One B-rep face of a CAD part: STEP entity #77526.
In plain terms, the planar face has unit normal (0, 0, 1).
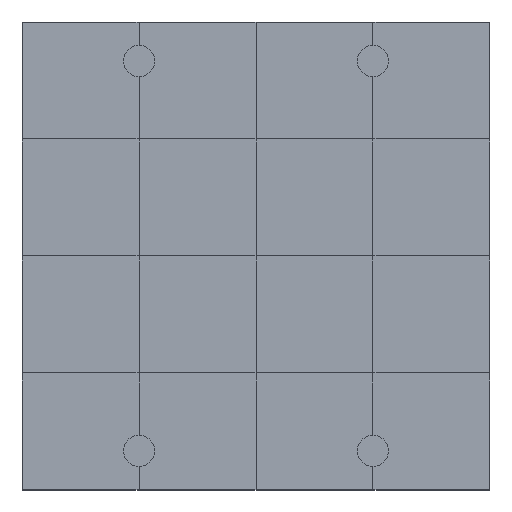
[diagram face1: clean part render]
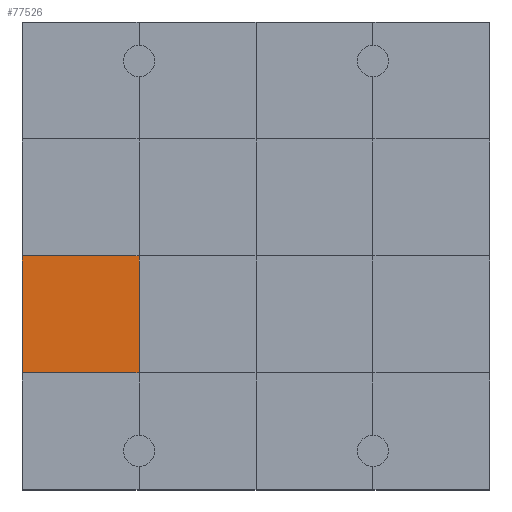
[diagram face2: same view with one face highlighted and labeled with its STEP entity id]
Its self-contained STEP definition (entity closure, numbers rounded to 3 decimals):
#77076 = VERTEX_POINT('',#77077);
#77077 = CARTESIAN_POINT('',(0.,3.,1.2));
#77091 = PLANE('',#77092);
#77092 = AXIS2_PLACEMENT_3D('',#77093,#77094,#77095);
#77093 = CARTESIAN_POINT('',(0.,3.,0.));
#77094 = DIRECTION('',(1.,0.,-0.));
#77095 = DIRECTION('',(0.,0.,1.));
#77117 = PLANE('',#77118);
#77118 = AXIS2_PLACEMENT_3D('',#77119,#77120,#77121);
#77119 = CARTESIAN_POINT('',(0.,0.,1.2));
#77120 = DIRECTION('',(0.,0.,1.));
#77121 = DIRECTION('',(1.,0.,-0.));
#77268 = VERTEX_POINT('',#77269);
#77269 = CARTESIAN_POINT('',(3.,3.,1.2));
#77290 = EDGE_CURVE('',#77076,#77268,#77291,.T.);
#77291 = SURFACE_CURVE('',#77292,(#77296,#77303),.PCURVE_S1.);
#77292 = LINE('',#77293,#77294);
#77293 = CARTESIAN_POINT('',(0.,3.,1.2));
#77294 = VECTOR('',#77295,1.);
#77295 = DIRECTION('',(1.,0.,-0.));
#77296 = PCURVE('',#77117,#77297);
#77297 = DEFINITIONAL_REPRESENTATION('',(#77298),#77302);
#77298 = LINE('',#77299,#77300);
#77299 = CARTESIAN_POINT('',(0.,3.));
#77300 = VECTOR('',#77301,1.);
#77301 = DIRECTION('',(1.,0.));
#77302 = ( GEOMETRIC_REPRESENTATION_CONTEXT(2) 
PARAMETRIC_REPRESENTATION_CONTEXT() REPRESENTATION_CONTEXT('2D SPACE',''
  ) );
#77303 = PCURVE('',#77304,#77309);
#77304 = PLANE('',#77305);
#77305 = AXIS2_PLACEMENT_3D('',#77306,#77307,#77308);
#77306 = CARTESIAN_POINT('',(0.,3.,1.2));
#77307 = DIRECTION('',(0.,0.,1.));
#77308 = DIRECTION('',(1.,0.,-0.));
#77309 = DEFINITIONAL_REPRESENTATION('',(#77310),#77314);
#77310 = LINE('',#77311,#77312);
#77311 = CARTESIAN_POINT('',(0.,0.));
#77312 = VECTOR('',#77313,1.);
#77313 = DIRECTION('',(1.,0.));
#77314 = ( GEOMETRIC_REPRESENTATION_CONTEXT(2) 
PARAMETRIC_REPRESENTATION_CONTEXT() REPRESENTATION_CONTEXT('2D SPACE',''
  ) );
#77349 = VERTEX_POINT('',#77350);
#77350 = CARTESIAN_POINT('',(0.,6.,1.2));
#77376 = EDGE_CURVE('',#77076,#77349,#77377,.T.);
#77377 = SURFACE_CURVE('',#77378,(#77382,#77389),.PCURVE_S1.);
#77378 = LINE('',#77379,#77380);
#77379 = CARTESIAN_POINT('',(0.,3.,1.2));
#77380 = VECTOR('',#77381,1.);
#77381 = DIRECTION('',(-0.,1.,0.));
#77382 = PCURVE('',#77091,#77383);
#77383 = DEFINITIONAL_REPRESENTATION('',(#77384),#77388);
#77384 = LINE('',#77385,#77386);
#77385 = CARTESIAN_POINT('',(1.2,0.));
#77386 = VECTOR('',#77387,1.);
#77387 = DIRECTION('',(0.,-1.));
#77388 = ( GEOMETRIC_REPRESENTATION_CONTEXT(2) 
PARAMETRIC_REPRESENTATION_CONTEXT() REPRESENTATION_CONTEXT('2D SPACE',''
  ) );
#77389 = PCURVE('',#77304,#77390);
#77390 = DEFINITIONAL_REPRESENTATION('',(#77391),#77395);
#77391 = LINE('',#77392,#77393);
#77392 = CARTESIAN_POINT('',(0.,0.));
#77393 = VECTOR('',#77394,1.);
#77394 = DIRECTION('',(0.,1.));
#77395 = ( GEOMETRIC_REPRESENTATION_CONTEXT(2) 
PARAMETRIC_REPRESENTATION_CONTEXT() REPRESENTATION_CONTEXT('2D SPACE',''
  ) );
#77526 = ADVANCED_FACE('',(#77527),#77304,.T.);
#77527 = FACE_BOUND('',#77528,.T.);
#77528 = EDGE_LOOP('',(#77529,#77530,#77531,#77559));
#77529 = ORIENTED_EDGE('',*,*,#77376,.F.);
#77530 = ORIENTED_EDGE('',*,*,#77290,.T.);
#77531 = ORIENTED_EDGE('',*,*,#77532,.T.);
#77532 = EDGE_CURVE('',#77268,#77533,#77535,.T.);
#77533 = VERTEX_POINT('',#77534);
#77534 = CARTESIAN_POINT('',(3.,6.,1.2));
#77535 = SURFACE_CURVE('',#77536,(#77540,#77547),.PCURVE_S1.);
#77536 = LINE('',#77537,#77538);
#77537 = CARTESIAN_POINT('',(3.,3.,1.2));
#77538 = VECTOR('',#77539,1.);
#77539 = DIRECTION('',(-0.,1.,0.));
#77540 = PCURVE('',#77304,#77541);
#77541 = DEFINITIONAL_REPRESENTATION('',(#77542),#77546);
#77542 = LINE('',#77543,#77544);
#77543 = CARTESIAN_POINT('',(3.,0.));
#77544 = VECTOR('',#77545,1.);
#77545 = DIRECTION('',(0.,1.));
#77546 = ( GEOMETRIC_REPRESENTATION_CONTEXT(2) 
PARAMETRIC_REPRESENTATION_CONTEXT() REPRESENTATION_CONTEXT('2D SPACE',''
  ) );
#77547 = PCURVE('',#77548,#77553);
#77548 = PLANE('',#77549);
#77549 = AXIS2_PLACEMENT_3D('',#77550,#77551,#77552);
#77550 = CARTESIAN_POINT('',(3.,3.,1.2));
#77551 = DIRECTION('',(0.,0.,1.));
#77552 = DIRECTION('',(1.,0.,-0.));
#77553 = DEFINITIONAL_REPRESENTATION('',(#77554),#77558);
#77554 = LINE('',#77555,#77556);
#77555 = CARTESIAN_POINT('',(0.,0.));
#77556 = VECTOR('',#77557,1.);
#77557 = DIRECTION('',(0.,1.));
#77558 = ( GEOMETRIC_REPRESENTATION_CONTEXT(2) 
PARAMETRIC_REPRESENTATION_CONTEXT() REPRESENTATION_CONTEXT('2D SPACE',''
  ) );
#77559 = ORIENTED_EDGE('',*,*,#77560,.F.);
#77560 = EDGE_CURVE('',#77349,#77533,#77561,.T.);
#77561 = SURFACE_CURVE('',#77562,(#77566,#77573),.PCURVE_S1.);
#77562 = LINE('',#77563,#77564);
#77563 = CARTESIAN_POINT('',(0.,6.,1.2));
#77564 = VECTOR('',#77565,1.);
#77565 = DIRECTION('',(1.,0.,-0.));
#77566 = PCURVE('',#77304,#77567);
#77567 = DEFINITIONAL_REPRESENTATION('',(#77568),#77572);
#77568 = LINE('',#77569,#77570);
#77569 = CARTESIAN_POINT('',(0.,3.));
#77570 = VECTOR('',#77571,1.);
#77571 = DIRECTION('',(1.,0.));
#77572 = ( GEOMETRIC_REPRESENTATION_CONTEXT(2) 
PARAMETRIC_REPRESENTATION_CONTEXT() REPRESENTATION_CONTEXT('2D SPACE',''
  ) );
#77573 = PCURVE('',#77574,#77579);
#77574 = PLANE('',#77575);
#77575 = AXIS2_PLACEMENT_3D('',#77576,#77577,#77578);
#77576 = CARTESIAN_POINT('',(0.,6.,1.2));
#77577 = DIRECTION('',(0.,0.,1.));
#77578 = DIRECTION('',(1.,0.,-0.));
#77579 = DEFINITIONAL_REPRESENTATION('',(#77580),#77584);
#77580 = LINE('',#77581,#77582);
#77581 = CARTESIAN_POINT('',(0.,0.));
#77582 = VECTOR('',#77583,1.);
#77583 = DIRECTION('',(1.,0.));
#77584 = ( GEOMETRIC_REPRESENTATION_CONTEXT(2) 
PARAMETRIC_REPRESENTATION_CONTEXT() REPRESENTATION_CONTEXT('2D SPACE',''
  ) );
